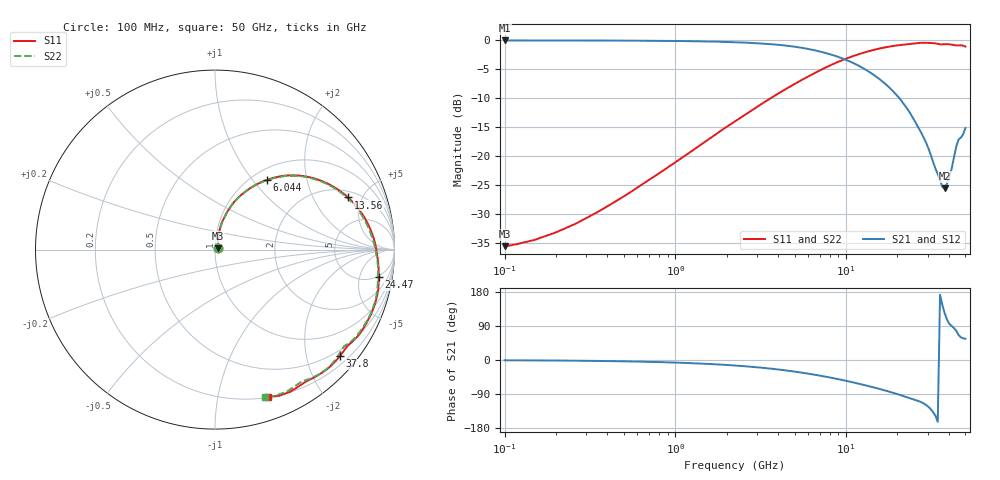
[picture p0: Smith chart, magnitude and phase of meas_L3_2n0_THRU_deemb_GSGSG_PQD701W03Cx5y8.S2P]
!  2-Port S-parameters saved by WinCal
! VAR NAME=L3_THRU_deemb
! VAR ObjTypeName=DATASET
! VAR IndexType=Frequency
! VAR FILENAME=meas_L3_THRU_deemb_GSGSG_meas_L1_0n4_THRU_deemb_GSGSG_PQD701W03Cx5y8.S2P.S2P
# Hz S RI R 50
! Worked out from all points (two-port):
!   201 points, 100 MHz to 50 GHz, reference 50 ohm
!   highest |S21| = -0.13 dB at 100 MHz (marker M1); lowest = -25.5 dB at 37.8 GHz (marker M2)
!   |S21| within 3 dB of the highest: start of sweep to 9.352 GHz
!   lowest |S11| = -35.5 dB at 100 MHz (marker M3), VSWR 1.03, Z = 51.5 + j0.853 ohm
!   |S11| at or under -10 dB: start of sweep to 3.638 GHz
!   |S22| runs from -35.5 to -0.5 dB; largest |S21 - S12| = 0.00034
!   S11 on the Smith chart (normalised r, x): 100 MHz: 1.03, +0.02; 6.044 GHz: 1.17, +1.19; 13.56 GHz: 2.42, +3.84; 24.47 GHz: 5, -10; 37.8 GHz: 0.37, -2.66; 50 GHz: 0.20, -1.41
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1e8  0.0146 0.00828  0.9853 -0.012  0.9851 -0.0119  0.0146 0.00828
1.544998e8  0.0145 0.0128  0.9848 -0.0185  0.9847 -0.0185  0.0145 0.0128
2.876239e8  0.0148 0.0242  0.9838 -0.0343  0.9838 -0.0345  0.0147 0.0241
8.019641e8  0.0184 0.0686  0.9743 -0.0938  0.9741 -0.0938  0.0185 0.0686
2.236068e9  0.0572 0.1902  0.9217 -0.2387  0.9216 -0.2387  0.0575 0.1898
3.792254e9  0.1383 0.298  0.8338 -0.3665  0.8336 -0.3664  0.1383 0.2968
6.043941e9  0.2911 0.389  0.6702 -0.4915  0.6702 -0.4915  0.2916 0.3875
6.431465e9  0.3187 0.3979  0.6407 -0.5053  0.6406 -0.5053  0.3192 0.3963
9.632587e9  0.5409 0.3998  0.41 -0.5503  0.4099 -0.5502  0.5413 0.3969
1.355771e10  0.7415 0.2904  0.1918 -0.4976  0.1918 -0.4975  0.7409 0.2853
1.793246e10  0.8654 0.1134  0.0429 -0.3858  0.0429 -0.3858  0.8612 0.107
2.094663e10  0.9007 -0.0136  -0.0159 -0.3025  -0.0159 -0.3025  0.8976 -0.0172
2.446744e10  0.9125 -0.1532  -0.049 -0.2114  -0.0489 -0.2114  0.908 -0.1611
2.948204e10  0.8714 -0.3548  -0.0626 -0.1132  -0.0625 -0.1132  0.8643 -0.3652
3.338389e10  0.7927 -0.4857  -0.0657 -0.0422  -0.0657 -0.0421  0.7783 -0.4951
3.664557e10  0.7196 -0.5614  -0.0445 0.031  -0.0445 0.031  0.7046 -0.5594
3.780214e10  0.6953 -0.5946  -0.0293 0.044  -0.0294 0.0439  0.6858 -0.5937
4.149549e10  0.5918 -0.6888  -0.000108 0.0773  -0.000171 0.0773  0.5763 -0.697
4.415609e10  0.5081 -0.734  0.0265 0.117  0.0265 0.117  0.4846 -0.7342
4.554969e10  0.4694 -0.7601  0.0551 0.1269  0.0551 0.1268  0.4514 -0.7568
4.847024e10  0.3571 -0.8146  0.0824 0.1294  0.0822 0.1294  0.3398 -0.8138
5e10  0.2977 -0.8207  0.0975 0.1445  0.0974 0.1446  0.2779 -0.8211
